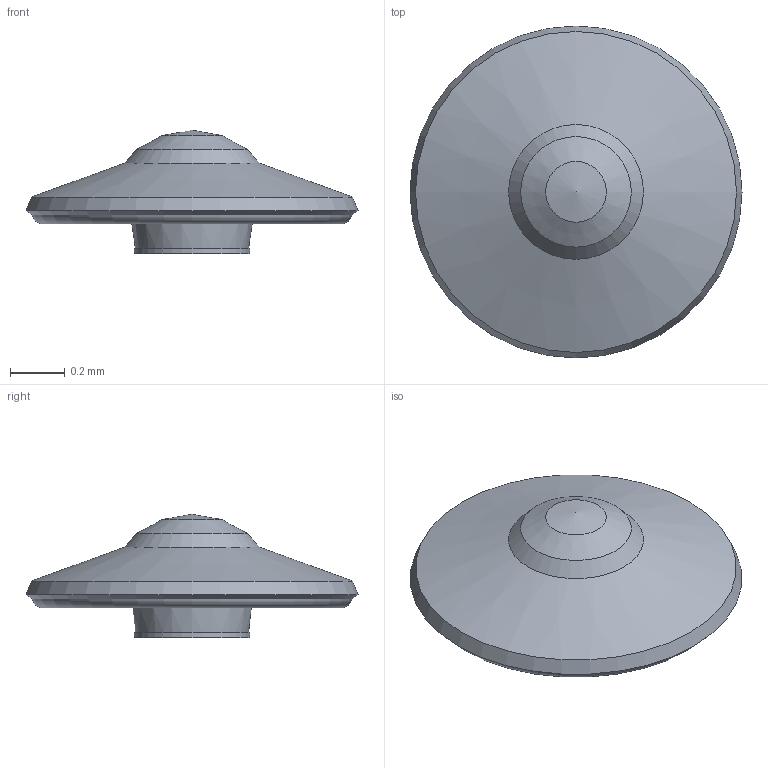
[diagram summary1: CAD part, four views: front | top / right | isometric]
STEP (ISO 10303-21) file: header records copied from the file, then geometry measured from it (millimetres).
FILE_DESCRIPTION(('Open CASCADE Model'),'2;1');
FILE_NAME('Open CASCADE Shape Model','2026-10-04T09:01:24',('Author'),( 'Open CASCADE'),'Open CASCADE STEP processor 7.9','Open CASCADE 7.9' ,'Unknown');
FILE_SCHEMA(('AUTOMOTIVE_DESIGN { 1 0 10303 214 1 1 1 1 }'));
Length unit declared in the file: millimetre
Products named in the file (16): SP-ORG-entry; capsule_backshell; nose; flexible_TPS; inflatable_torus_1; inflatable_torus_2; inflatable_torus_3; inflatable_torus_4; sample_drawer; sample_cassette_1; sample_cassette_2; optical_window; capsule_avionics_and_hold_battery; parachute_canister; recovery_beacon; separation_interface
Assembly tree (15 placements, depth 2):
  SP-ORG-entry
    capsule_backshell
    nose
    flexible_TPS
    inflatable_torus_1
    inflatable_torus_2
    inflatable_torus_3
    inflatable_torus_4
    sample_drawer
    sample_cassette_1
    sample_cassette_2
    optical_window
    capsule_avionics_and_hold_battery
    parachute_canister
    recovery_beacon
    separation_interface
Bounding box: 1.21 x 1.21 x 0.45 mm (x, y, z)
Volume: 0.2 mm3; surface area: 7 mm2
Topology: 15 solids, 15 shells, 56 faces, 99 edges, 62 vertices
Faces by surface type: plane 39, cone 8, cylinder 5, torus 4
Full cylindrical faces by diameter (mm): 0.04 x1, 0.14 x1, 0.423 x1, 0.491 x2
Entity records: 3005 total; most frequent: DIRECTION 463, CARTESIAN_POINT 428, LINE 260, VECTOR 260, ORIENTED_EDGE 196, PCURVE 196, DEFINITIONAL_REPRESENTATION 196, EDGE_CURVE 98
One B-rep face of a CAD part: STEP entity #459.
In plain terms, the conical face has half-angle 70 degrees and reference radius 0.246 mm.
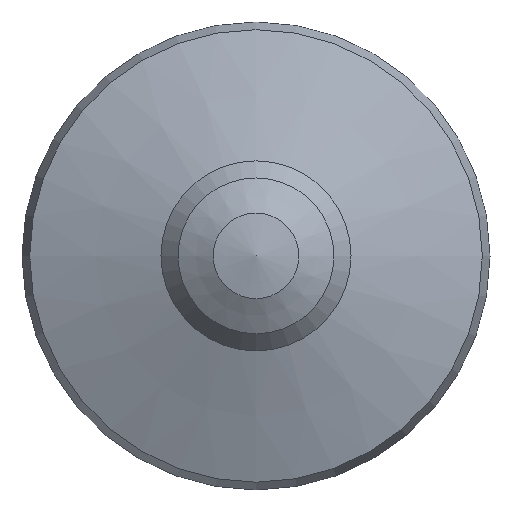
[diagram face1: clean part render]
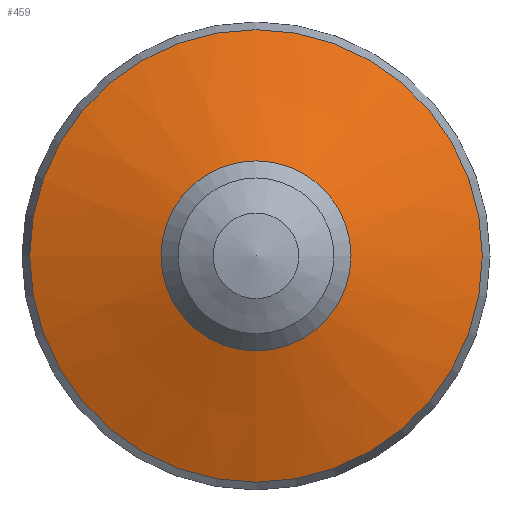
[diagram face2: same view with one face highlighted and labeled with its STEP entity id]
Its self-contained STEP definition (entity closure, numbers rounded to 3 decimals):
#459 = ADVANCED_FACE('',(#460),#473,.T.);
#460 = FACE_BOUND('',#461,.F.);
#461 = EDGE_LOOP('',(#462,#496,#519,#546));
#462 = ORIENTED_EDGE('',*,*,#463,.T.);
#463 = EDGE_CURVE('',#464,#464,#466,.T.);
#464 = VERTEX_POINT('',#465);
#465 = CARTESIAN_POINT('',(0.246,0.,0.33));
#466 = SURFACE_CURVE('',#467,(#472,#484),.PCURVE_S1.);
#467 = CIRCLE('',#468,0.246);
#468 = AXIS2_PLACEMENT_3D('',#469,#470,#471);
#469 = CARTESIAN_POINT('',(0.,0.,0.33));
#470 = DIRECTION('',(0.,0.,1.));
#471 = DIRECTION('',(1.,0.,-0.));
#472 = PCURVE('',#473,#478);
#473 = CONICAL_SURFACE('',#474,0.246,1.222);
#474 = AXIS2_PLACEMENT_3D('',#475,#476,#477);
#475 = CARTESIAN_POINT('',(0.,0.,0.33));
#476 = DIRECTION('',(-0.,-0.,-1.));
#477 = DIRECTION('',(1.,0.,0.));
#478 = DEFINITIONAL_REPRESENTATION('',(#479),#483);
#479 = LINE('',#480,#481);
#480 = CARTESIAN_POINT('',(-0.,0.));
#481 = VECTOR('',#482,1.);
#482 = DIRECTION('',(-1.,0.));
#483 = ( GEOMETRIC_REPRESENTATION_CONTEXT(2) 
PARAMETRIC_REPRESENTATION_CONTEXT() REPRESENTATION_CONTEXT('2D SPACE',''
  ) );
#484 = PCURVE('',#485,#490);
#485 = CYLINDRICAL_SURFACE('',#486,0.246);
#486 = AXIS2_PLACEMENT_3D('',#487,#488,#489);
#487 = CARTESIAN_POINT('',(0.,0.,0.305));
#488 = DIRECTION('',(0.,0.,1.));
#489 = DIRECTION('',(1.,0.,-0.));
#490 = DEFINITIONAL_REPRESENTATION('',(#491),#495);
#491 = LINE('',#492,#493);
#492 = CARTESIAN_POINT('',(0.,0.025));
#493 = VECTOR('',#494,1.);
#494 = DIRECTION('',(1.,0.));
#495 = ( GEOMETRIC_REPRESENTATION_CONTEXT(2) 
PARAMETRIC_REPRESENTATION_CONTEXT() REPRESENTATION_CONTEXT('2D SPACE',''
  ) );
#496 = ORIENTED_EDGE('',*,*,#497,.T.);
#497 = EDGE_CURVE('',#464,#498,#500,.T.);
#498 = VERTEX_POINT('',#499);
#499 = CARTESIAN_POINT('',(0.585,0.,0.207));
#500 = SEAM_CURVE('',#501,(#505,#512),.PCURVE_S1.);
#501 = LINE('',#502,#503);
#502 = CARTESIAN_POINT('',(0.246,0.,0.33));
#503 = VECTOR('',#504,1.);
#504 = DIRECTION('',(0.94,0.,-0.342));
#505 = PCURVE('',#473,#506);
#506 = DEFINITIONAL_REPRESENTATION('',(#507),#511);
#507 = LINE('',#508,#509);
#508 = CARTESIAN_POINT('',(-0.,0.));
#509 = VECTOR('',#510,1.);
#510 = DIRECTION('',(-0.,1.));
#511 = ( GEOMETRIC_REPRESENTATION_CONTEXT(2) 
PARAMETRIC_REPRESENTATION_CONTEXT() REPRESENTATION_CONTEXT('2D SPACE',''
  ) );
#512 = PCURVE('',#473,#513);
#513 = DEFINITIONAL_REPRESENTATION('',(#514),#518);
#514 = LINE('',#515,#516);
#515 = CARTESIAN_POINT('',(-6.283,0.));
#516 = VECTOR('',#517,1.);
#517 = DIRECTION('',(-0.,1.));
#518 = ( GEOMETRIC_REPRESENTATION_CONTEXT(2) 
PARAMETRIC_REPRESENTATION_CONTEXT() REPRESENTATION_CONTEXT('2D SPACE',''
  ) );
#519 = ORIENTED_EDGE('',*,*,#520,.F.);
#520 = EDGE_CURVE('',#498,#498,#521,.T.);
#521 = SURFACE_CURVE('',#522,(#527,#534),.PCURVE_S1.);
#522 = CIRCLE('',#523,0.585);
#523 = AXIS2_PLACEMENT_3D('',#524,#525,#526);
#524 = CARTESIAN_POINT('',(0.,0.,0.207));
#525 = DIRECTION('',(0.,0.,1.));
#526 = DIRECTION('',(1.,0.,-0.));
#527 = PCURVE('',#473,#528);
#528 = DEFINITIONAL_REPRESENTATION('',(#529),#533);
#529 = LINE('',#530,#531);
#530 = CARTESIAN_POINT('',(-0.,0.123));
#531 = VECTOR('',#532,1.);
#532 = DIRECTION('',(-1.,0.));
#533 = ( GEOMETRIC_REPRESENTATION_CONTEXT(2) 
PARAMETRIC_REPRESENTATION_CONTEXT() REPRESENTATION_CONTEXT('2D SPACE',''
  ) );
#534 = PCURVE('',#535,#540);
#535 = CONICAL_SURFACE('',#536,0.585,0.381);
#536 = AXIS2_PLACEMENT_3D('',#537,#538,#539);
#537 = CARTESIAN_POINT('',(0.,0.,0.207));
#538 = DIRECTION('',(-0.,-0.,-1.));
#539 = DIRECTION('',(1.,0.,0.));
#540 = DEFINITIONAL_REPRESENTATION('',(#541),#545);
#541 = LINE('',#542,#543);
#542 = CARTESIAN_POINT('',(-0.,0.));
#543 = VECTOR('',#544,1.);
#544 = DIRECTION('',(-1.,0.));
#545 = ( GEOMETRIC_REPRESENTATION_CONTEXT(2) 
PARAMETRIC_REPRESENTATION_CONTEXT() REPRESENTATION_CONTEXT('2D SPACE',''
  ) );
#546 = ORIENTED_EDGE('',*,*,#497,.F.);
